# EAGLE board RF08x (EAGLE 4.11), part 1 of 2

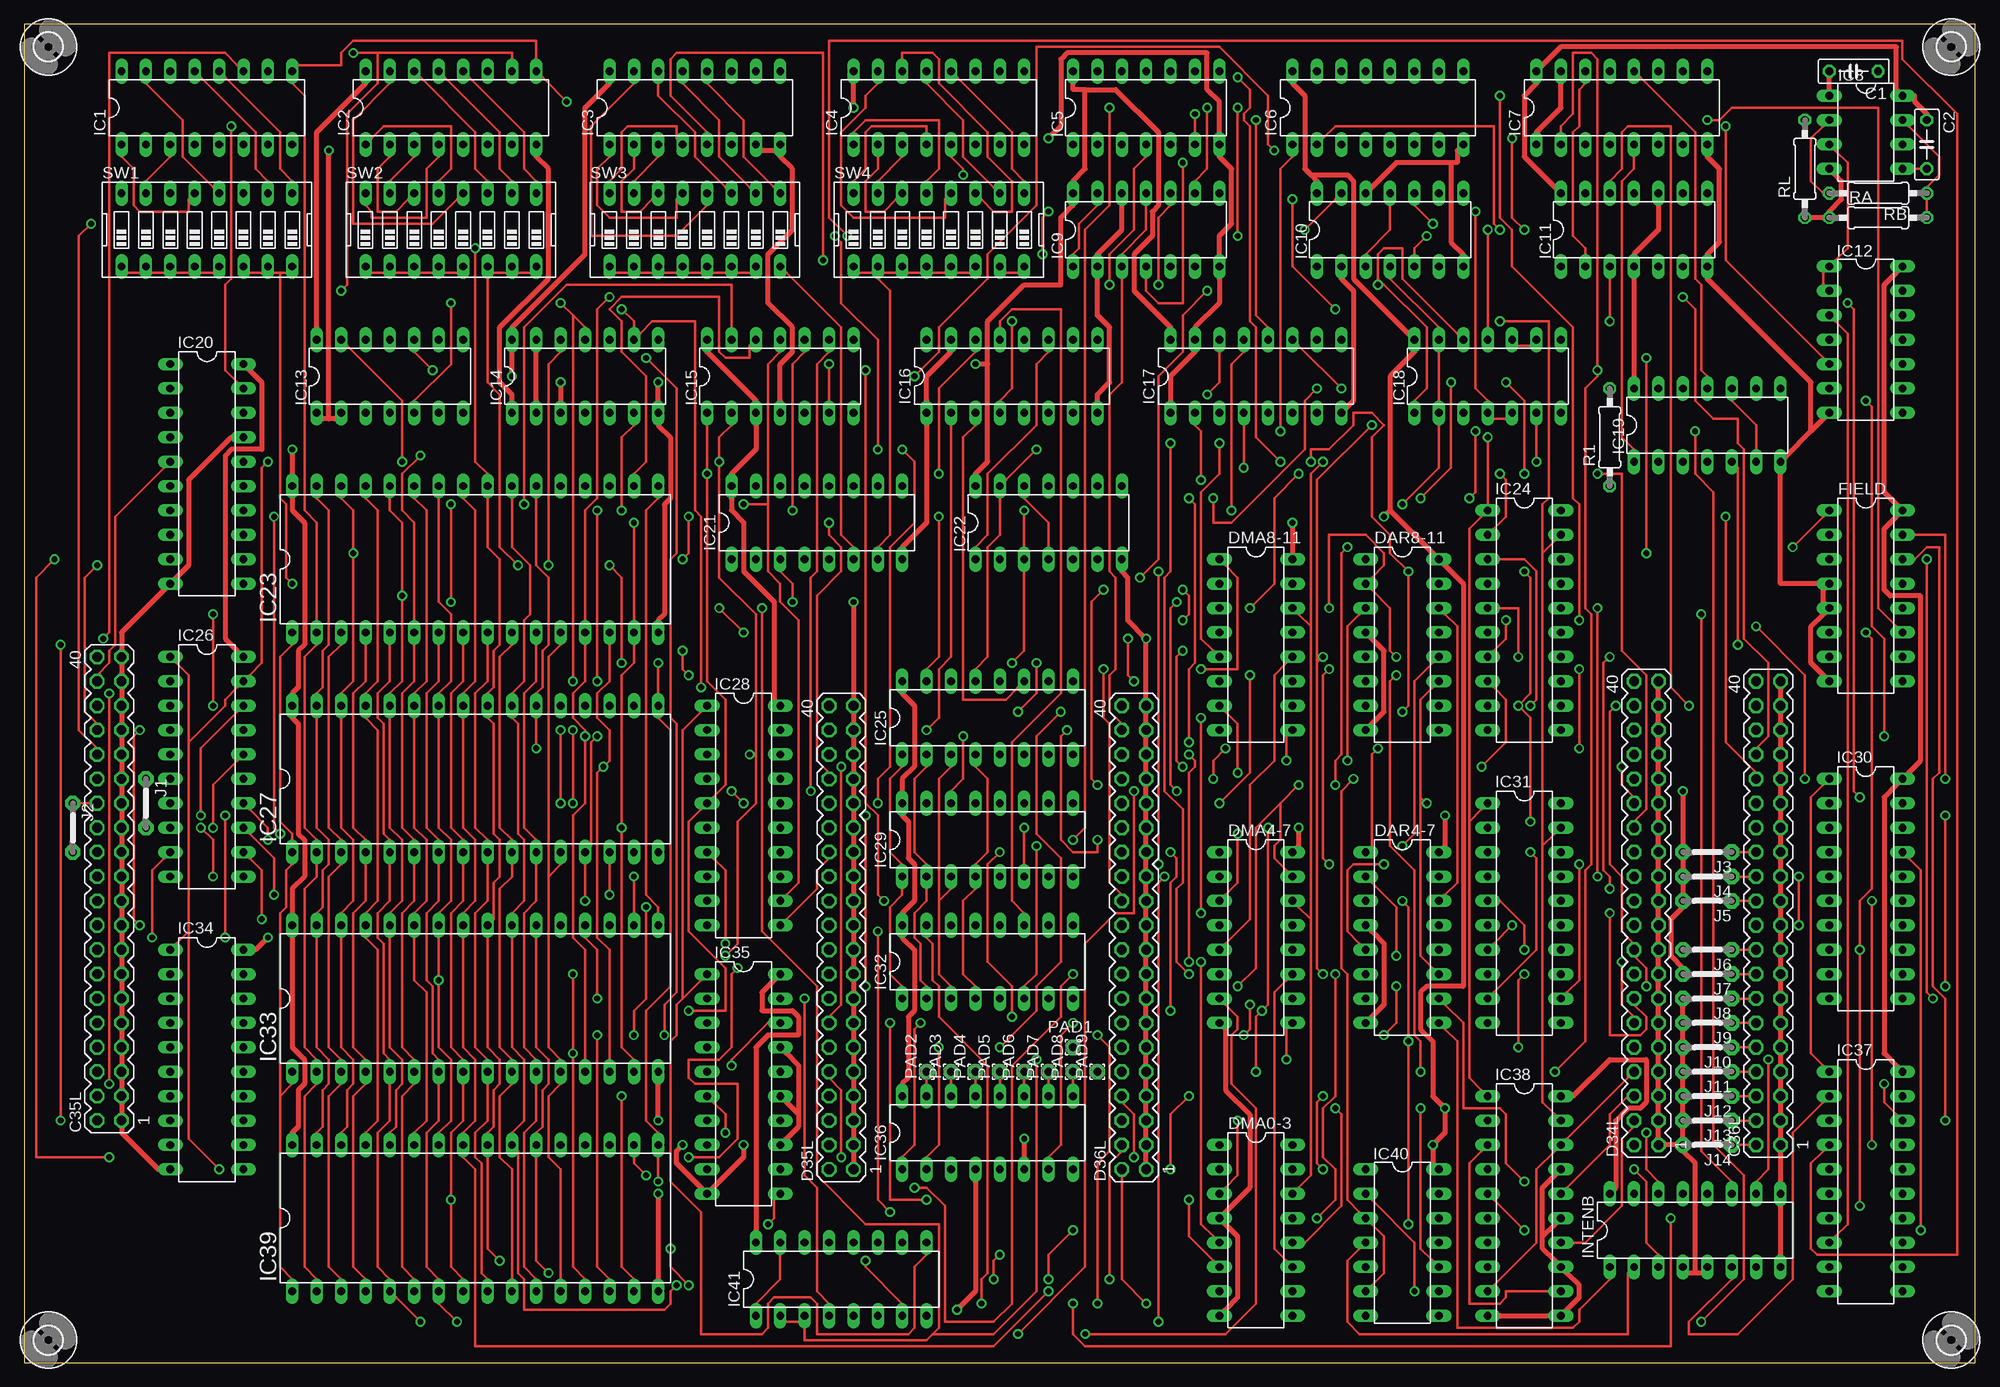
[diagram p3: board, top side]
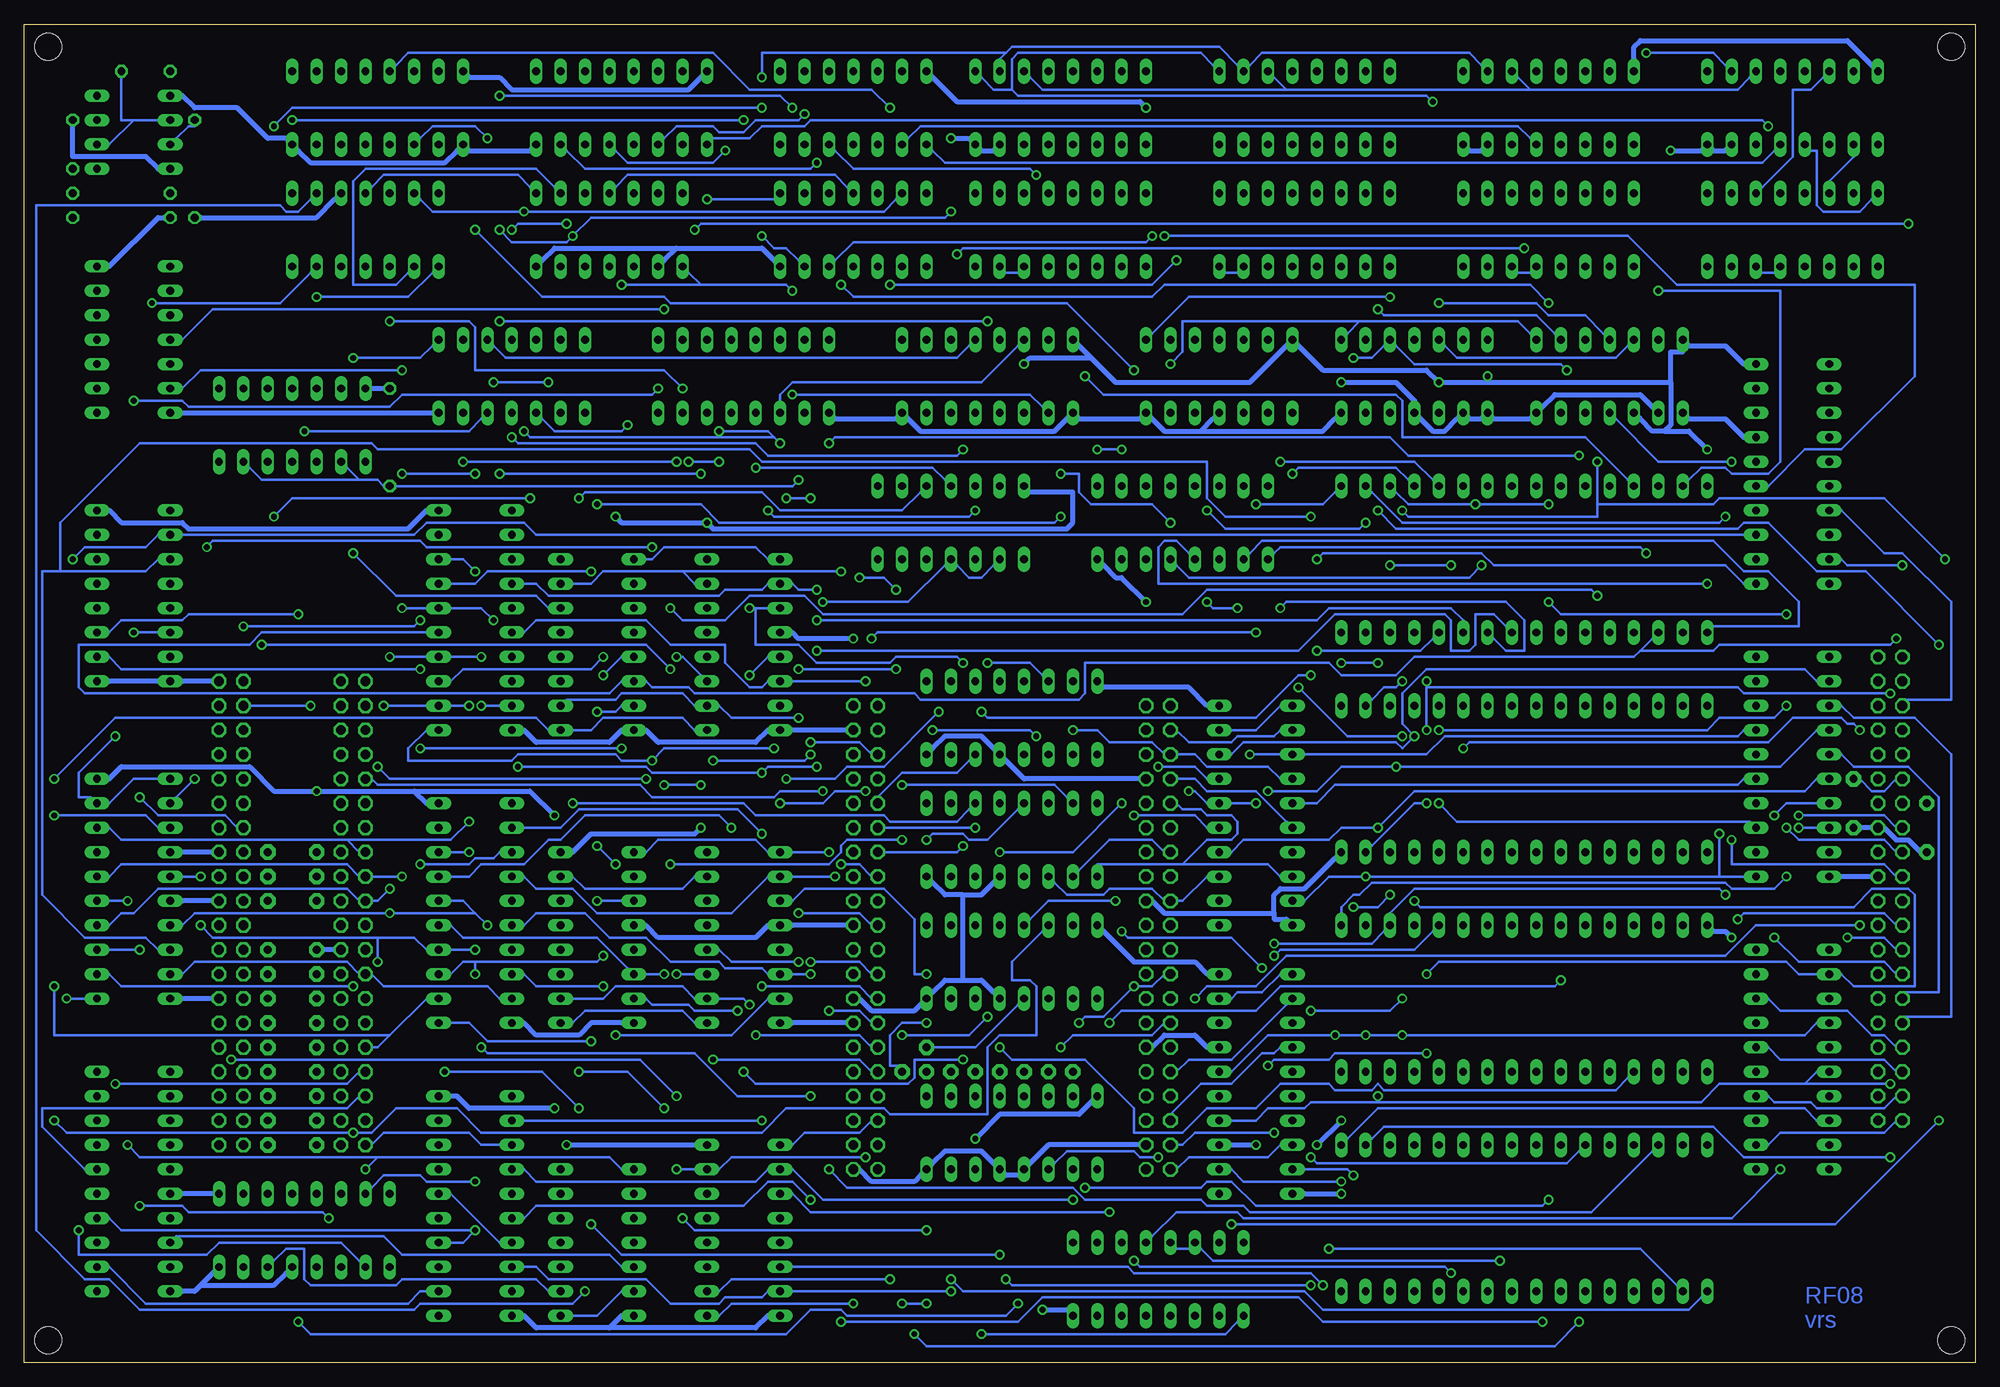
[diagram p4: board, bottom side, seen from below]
Size 203.18 x 139.37 mm. Coordinates in mm from the lower left corner, seen from the top.
Outline: 0,0 203.18,0 203.18,139.37 0,139.37 0,0
Copper layers (1*16): Top 0.035mm / dielectric 1.5mm / Bottom 0.035mm
Design rules "default": minimum track width 10mil, minimum drill 24mil, track to track 8mil, track to pad 8mil, pad to pad 8mil, via to via 8mil, smd to smd 8mil, copper to edge 40mil, drill to drill 8mil, minimum pad ring 10mil, minimum via ring 8mil, stop-mask expansion 4mil, vias tented up to drill 0mil, thermal gap 10mil
Net classes: 1 Power: width 0.508 mm

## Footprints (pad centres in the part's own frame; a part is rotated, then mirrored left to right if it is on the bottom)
C050-025X075 = drill 0.813 octagon: 1 -2.54,0; 2 2.54,0
MA20-2 = drill 1.016 octagon: 1 -24.13,-1.27; 2 -24.13,1.27; 3 -21.59,-1.27; 4 -21.59,1.27; 5 -19.05,-1.27; 6 -19.05,1.27; 7 -16.51,-1.27; 8 -16.51,1.27; 9 -13.97,-1.27; 10 -13.97,1.27; 11 -11.43,-1.27; 12 -11.43,1.27; 13 -8.89,-1.27; 14 -8.89,1.27; 15 -6.35,-1.27; 16 -6.35,1.27; 17 -3.81,-1.27; 18 -3.81,1.27; 19 -1.27,-1.27; 20 -1.27,1.27; 21 1.27,-1.27; 22 1.27,1.27; 23 3.81,-1.27; 24 3.81,1.27; 25 6.35,-1.27; 26 6.35,1.27; 27 8.89,-1.27; 28 8.89,1.27; 29 11.43,-1.27; 30 11.43,1.27; 31 13.97,-1.27; 32 13.97,1.27; 33 16.51,-1.27; 34 16.51,1.27; 35 19.05,-1.27; 36 19.05,1.27; 37 21.59,-1.27; 38 21.59,1.27; 39 24.13,-1.27; 40 24.13,1.27
DIL16 = drill 0.813 long: 1 -8.89,-3.81; 2 -6.35,-3.81; 3 -3.81,-3.81; 4 -1.27,-3.81; 5 1.27,-3.81; 6 3.81,-3.81; 7 6.35,-3.81; 8 8.89,-3.81; 9 8.89,3.81; 10 6.35,3.81; 11 3.81,3.81; 12 1.27,3.81; 13 -1.27,3.81; 14 -3.81,3.81; 15 -6.35,3.81; 16 -8.89,3.81
DIL14 = drill 0.813 long: 1 -7.62,-3.81; 2 -5.08,-3.81; 3 -2.54,-3.81; 4 0,-3.81; 5 2.54,-3.81; 6 5.08,-3.81; 7 7.62,-3.81; 8 7.62,3.81; 9 5.08,3.81; 10 2.54,3.81; 11 0,3.81; 12 -2.54,3.81; 13 -5.08,3.81; 14 -7.62,3.81
DIL08 = drill 0.813 long: 1 -3.81,-3.81; 2 -1.27,-3.81; 3 1.27,-3.81; 4 3.81,-3.81; 5 3.81,3.81; 6 1.27,3.81; 7 -1.27,3.81; 8 -3.81,3.81
DIL20 = drill 0.813 long: 1 -11.43,-3.81; 2 -8.89,-3.81; 3 -6.35,-3.81; 4 -3.81,-3.81; 5 -1.27,-3.81; 6 1.27,-3.81; 7 3.81,-3.81; 8 6.35,-3.81; 9 8.89,-3.81; 10 11.43,-3.81; 11 11.43,3.81; 12 8.89,3.81; 13 6.35,3.81; 14 3.81,3.81; 15 1.27,3.81; 16 -1.27,3.81; 17 -3.81,3.81; 18 -6.35,3.81; 19 -8.89,3.81; 20 -11.43,3.81
DIL32 = drill 0.813 long: 1 -19.05,-7.62; 2 -16.51,-7.62; 3 -13.97,-7.62; 4 -11.43,-7.62; 5 -8.89,-7.62; 6 -6.35,-7.62; 7 -3.81,-7.62; 8 -1.27,-7.62; 9 1.27,-7.62; 10 3.81,-7.62; 11 6.35,-7.62; 12 8.89,-7.62; 13 11.43,-7.62; 14 13.97,-7.62; 15 16.51,-7.62; 16 19.05,-7.62; 17 19.05,7.62; 18 16.51,7.62; 19 13.97,7.62; 20 11.43,7.62; 21 8.89,7.62; 22 6.35,7.62; 23 3.81,7.62; 24 1.27,7.62; 25 -1.27,7.62; 26 -3.81,7.62; 27 -6.35,7.62; 28 -8.89,7.62; 29 -11.43,7.62; 30 -13.97,7.62; 31 -16.51,7.62; 32 -19.05,7.62
05 = drill 0.813 pad 1.6 octagon: 1 -2.54,0; 2 2.54,0
1,6/0,8 = drill 0.813 pad 1.6 octagon: 1 0,0
0207/10 = drill 0.813 octagon: 1 -5.08,0; 2 5.08,0
EDG-08 = drill 0.813 long: 1 -8.89,-3.81; 2 -6.35,-3.81; 3 -3.81,-3.81; 4 -1.27,-3.81; 5 1.27,-3.81; 6 3.81,-3.81; 7 6.35,-3.81; 8 8.89,-3.81; 9 8.89,3.81; 10 6.35,3.81; 11 3.81,3.81; 12 1.27,3.81; 13 -1.27,3.81; 14 -3.81,3.81; 15 -6.35,3.81; 16 -8.89,3.81
2,8 = hole 2.8: 0,0

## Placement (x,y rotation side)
C1  .1uf  [C050-025X075]  190.5,134.46 180 top
C2  .1uf  [C050-025X075]  198.12,126.83 270 top
C35L  [MA20-2]  8.88,49.37 90 top
C36L  [MA20-2]  181.61,46.83 90 top
D34L  [MA20-2]  168.91,46.83 90 top
D35L  [MA20-2]  85.09,44.29 90 top
D36L  [MA20-2]  115.56,44.29 90 top
DAR4-7  74LS193N  [DIL16]  143.5,44.29 270 top
DAR8-11  74LS193N  [DIL16]  143.5,74.77 270 top
DMA0-3  74LS193N  [DIL16]  128.27,13.81 270 top
DMA4-7  74LS193N  [DIL16]  128.27,44.29 270 top
DMA8-11  74LS193N  [DIL16]  128.27,74.77 270 top
FIELD  74LS193N  [DIL16]  191.77,79.84 270 top
IC1  74LS151N  [DIL16]  19.05,130.65 0 top
IC2  74LS151N  [DIL16]  44.45,130.65 0 top
IC3  74LS151N  [DIL16]  69.84,130.65 0 top
IC4  74LS151N  [DIL16]  95.25,130.65 0 top
IC5  74LS20N  [DIL14]  116.84,130.65 0 top
IC6  74S139N  [DIL16]  140.97,130.65 0 top
IC7  74LS139N  [DIL16]  166.37,130.65 0 top
IC8  LM555N  [DIL08]  191.77,128.11 270 top
IC9  74S74N  [DIL14]  116.84,117.94 0 top
IC10  74S74N  [DIL14]  142.24,117.94 0 top
IC11  74S74N  [DIL14]  167.63,117.94 0 top
IC12  74LS00N  [DIL14]  191.77,106.52 270 top
IC13  74180N  [DIL14]  38.09,102.7 0 top
IC14  74180N  [DIL14]  58.41,102.7 0 top
IC15  74180N  [DIL14]  78.73,102.7 0 top
IC16  74S139N  [DIL16]  102.87,102.7 0 top
IC17  74S139N  [DIL16]  128.27,102.7 0 top
IC18  74LS00N  [DIL14]  152.4,102.7 0 top
IC19  7407N  [DIL14]  175.25,97.62 0 top
IC20  74S240N  [DIL20]  19.05,92.54 270 top
IC21  74LS139N  [DIL16]  82.55,87.46 0 top
IC22  7407N  [DIL14]  106.68,87.46 0 top
IC23  628512  [DIL32]  46.98,83.65 0 top
IC24  74S240N  [DIL20]  156.21,77.3 270 top
IC25  74S138N  [DIL16]  100.33,67.14 0 top
IC26  74S240N  [DIL20]  19.05,62.06 270 top
IC27  628512  [DIL32]  46.98,60.8 0 top
IC28  74LS244N  [DIL20]  74.93,56.98 270 top
IC29  74S138N  [DIL16]  100.33,54.45 0 top
IC30  74S240N  [DIL20]  191.77,49.37 270 top
IC31  74S240N  [DIL20]  156.21,46.83 270 top
IC32  74S138N  [DIL16]  100.33,41.74 0 top
IC33  628512  [DIL32]  46.98,37.94 0 top
IC34  74S240N  [DIL20]  19.05,31.59 270 top
IC35  74LS244N  [DIL20]  74.93,29.05 270 top
IC36  74S138N  [DIL16]  100.33,23.96 0 top
IC37  74S240N  [DIL20]  191.77,18.89 270 top
IC38  74S240N  [DIL20]  156.21,16.35 270 top
IC39  628512  [DIL32]  46.98,15.08 0 top
IC40  74S03N  [DIL14]  143.5,12.54 270 top
IC41  74LS139N  [DIL16]  85.09,8.73 0 top
INTENB  74LS193N  [DIL16]  173.99,13.81 0 top
J1  J5MM  [05]  12.69,58.26 270 top
J2  J5MM  [05]  5.08,55.72 270 top
J3  J5MM  [05]  175.25,53.18 180 top
J4  J5MM  [05]  175.25,50.63 180 top
J5  J5MM  [05]  175.25,48.09 180 top
J6  J5MM  [05]  175.25,43.02 180 top
J7  J5MM  [05]  175.25,40.48 180 top
J8  J5MM  [05]  175.25,37.94 180 top
J9  J5MM  [05]  175.25,35.4 180 top
J10  J5MM  [05]  175.25,32.86 180 top
J11  J5MM  [05]  175.25,30.32 180 top
J12  J5MM  [05]  175.25,27.78 180 top
J13  J5MM  [05]  175.25,25.23 180 top
J14  J5MM  [05]  175.25,22.7 180 top
PAD1  [1,6/0,8]  109.22,32.86 90 top
PAD2  [1,6/0,8]  93.98,30.32 90 top
PAD3  [1,6/0,8]  96.52,30.32 90 top
PAD4  [1,6/0,8]  99.06,30.32 90 top
PAD5  [1,6/0,8]  101.59,30.32 90 top
PAD6  [1,6/0,8]  104.14,30.32 90 top
PAD7  [1,6/0,8]  106.68,30.32 90 top
PAD8  [1,6/0,8]  109.22,30.32 90 top
PAD9  [1,6/0,8]  111.76,30.32 90 top
R1  5.1K  [0207/10]  165.09,96.35 90 top
RA  470K  [0207/10]  193.03,119.21 0 top
RB  1.5K  [0207/10]  193.03,121.75 180 top
RL  1K  [0207/10]  185.41,124.29 90 top
SW1  [EDG-08]  19.05,117.94 0 top
SW2  [EDG-08]  44.45,117.94 0 top
SW3  [EDG-08]  69.84,117.94 0 top
SW4  [EDG-08]  95.25,117.94 0 top
U$1  [2,8]  2.54,137 0 top
U$2  [2,8]  200.66,137 0 top
U$3  [2,8]  2.54,2.38 0 top
U$4  [2,8]  200.66,2.38 0 top

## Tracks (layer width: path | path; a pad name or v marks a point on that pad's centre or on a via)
3CYC\
  Top 0.254: C35L.28 6.98,58.26 5.71,58.26 J2.1
601\  (via drill 0.61)
  Top 0.254: IC9.1 109.22,115.4 109.85,116.04 109.85,118.58 111.76,120.48 IC9.13 | v99.69,6.18 99.69,8.73 100.33,9.36 100.33,30.95 95.25,36.03 95.25,39.2 94.61,39.84 94.61,43.65 93.98,44.29 IC32.15 | v174.62,4.28 179.06,8.73 179.06,19.52 175.89,22.7 175.89,90.64 173.99,92.54 v173.99,96.99 | IC18.5 154.3,98.26 153.03,98.26 IC18.4 152.4,100.16 151.12,101.43 v151.12,119.85
  Bottom 0.254: IC11.13 161.92,121.12 160.65,119.85 v151.12,119.85 113.66,119.85 112.39,121.12 IC9.13 | v99.69,6.18 100.96,4.92 117.47,4.92 118.11,5.55 121.28,5.55 123.82,3.01 173.35,3.01 v174.62,4.28 | v173.99,96.99 156.84,96.99 155.57,98.26 IC18.5
602\  (via drill 0.61)
  Top 0.254: 141.6,112.23 140.97,112.86 140.97,115.4 141.6,116.04 143.5,116.04 143.5,112.86 149.22,107.15 IC18.12 | 141.6,112.23 146.05,107.78 146.05,101.43 144.78,100.16 IC18.1 | v111.76,60.16 111.12,60.8 111.12,79.21 v112.39,80.48 | v116.2,81.75 118.11,83.65 118.11,102.7 120.65,105.24 120.65,109.05 v123.19,111.59 | 141.6,112.23 v140.97,112.23
  Bottom 0.254: v111.76,60.16 95.88,60.16 94.61,58.89 IC29.15 | v112.39,80.48 113.66,81.75 v116.2,81.75 | v123.19,111.59 123.82,112.23 132.71,112.23 | 132.71,112.23 133.98,113.5 IC10.1 | v140.97,112.23 132.71,112.23
604\  (via drill 0.61)
  Top 0.254: v95.25,88.1 95.25,73.49 93.98,72.22 IC25.15 | v143.5,89.37 147.31,93.18 147.31,97.62 IC18.2 147.31,100.16 147.31,105.24 IC18.13 147.31,107.78 142.24,112.86 IC10.4
  Bottom 0.254: v95.25,88.1 95.88,87.46 130.81,87.46 132.71,89.37 v143.5,89.37
611\  (via drill 0.61)
  Top 0.254: v168.91,23.96 168.91,20.16 170.18,18.89 INTENB.14 | v200.02,25.23 200.02,37.94 198.75,39.2 198.75,60.8 199.38,61.43 199.38,84.92 198.12,84.92 196.84,83.65 FIELD.14
  Bottom 0.254: IC32.14 97.15,44.92 100.33,41.74 100.33,39.84 98.42,39.84 97.79,39.2 97.79,34.12 101.59,34.12 102.87,32.86 102.87,25.87 113.03,25.87 113.66,26.51 123.82,26.51 126.36,23.96 155.57,23.96 158.11,26.51 164.46,26.51 167,23.96 v168.91,23.96 198.75,23.96 v200.02,25.23
612\  (via drill 0.61)
  Top 0.254: v97.79,65.24 97.79,60.8 96.52,59.52 IC29.14 | v108.58,65.88 107.95,65.24 107.95,54.45 109.22,53.18 111.76,53.18 v111.76,54.45 | v135.88,51.91 135.25,52.54 135.25,71.59 v135.88,72.22 | v178.43,74.77 178.43,93.18 IC19.5
  Bottom 0.254: v97.79,65.24 98.42,65.88 v108.58,65.88 | v111.76,54.45 117.47,54.45 118.11,53.81 118.11,53.18 119.38,51.91 v135.88,51.91 | v135.88,72.22 138.43,74.77 v178.43,74.77
614\  (via drill 0.61)
  Top 0.254: v102.87,72.86 104.14,74.13 104.14,82.38 IC22.3 104.14,84.92 v104.14,88.73 | v125.73,88.73 125.73,103.97 127,105.24 IC17.13
  Bottom 0.254: v102.87,72.86 98.42,72.86 97.15,71.59 IC25.14 | v125.73,88.73 125.09,88.1 104.77,88.1 v104.14,88.73
621\  (via drill 0.61)
  Top 0.254: v89.53,48.09 88.9,48.73 88.9,56.98 87.62,58.26 v87.62,103.34 | v156.21,117.94 154.94,119.21 v154.94,127.47
  Bottom 0.254: v89.53,48.09 96.52,48.09 98.42,46.19 IC32.13 | v87.62,103.34 94.61,110.32 135.88,110.32 136.52,110.96 149.22,110.96 v156.21,117.94 | v154.94,127.47 156.21,128.74 160.65,128.74 161.92,127.47 IC7.3
622\  (via drill 0.61)
  Top 0.254: v109.22,54.45 110.48,55.72 110.48,117.94 113.03,120.48 v113.03,130.65
  Bottom 0.254: v109.22,54.45 108.58,55.08 105.41,55.08 104.77,54.45 102.87,54.45 99.69,57.62 IC29.13 | v113.03,130.65 114.93,132.55 127.63,132.55 131.44,136.36 163.19,136.36 164.46,135.09 IC7.13
624\  (via drill 0.61)
  Top 0.254: IC25.13 99.06,72.22 100.33,73.49 100.33,84.92 101.59,86.19 101.59,90 IC22.13 102.23,91.91 v105.41,95.08 | 150.49,56.35 150.49,29.68 151.76,28.41 IC38.1 | 150.49,56.35 151.76,57.62 IC31.1 | 150.49,56.35 150.49,86.83 151.76,88.1 IC24.1 152.4,89.37 v152.4,96.35
  Bottom 0.254: v105.41,95.08 106.04,94.45 125.73,94.45 127,95.72 151.76,95.72 v152.4,96.35
641\
  Top 0.254: IC16.13 101.59,107.78 101.59,108.42 102.87,109.69 107.95,109.69 107.95,69.68 102.87,64.6 102.87,48.09 104.14,46.83 IC32.11
642\  (via drill 0.61)
  Top 0.254: v146.05,58.26 145.41,58.89 | 145.41,58.89 145.41,69.05 146.68,70.32 DAR8-11.11 | 145.41,58.89 145.41,42.38 146.68,41.11 DAR4-7.11
  Bottom 0.254: v146.05,58.26 128.27,58.26 127,56.98 113.66,56.98 113.03,56.35 106.04,56.35 104.77,57.62 IC29.11
644\
  Top 0.254: IC25.11 103.5,70.32 102.23,69.05 97.79,69.05 97.79,96.35 99.06,97.62 IC16.3
645\  (via drill 0.61)
  Top 0.254: 158.11,53.81 158.11,27.14 159.38,25.87 IC38.19 | 158.11,53.81 159.38,55.08 IC31.19 | 158.11,84.29 159.38,85.56 IC24.19 | 158.11,84.29 158.11,53.81 | v102.87,108.42 102.87,101.43 101.59,100.16 IC16.4 | v153.66,108.42 158.75,108.42 158.75,90 158.11,89.37 158.11,84.29
  Bottom 0.254: v153.66,108.42 v102.87,108.42
ACB00\
  Top 0.254: IC38.12 158.75,7.46 154.3,7.46 154.3,6.82 153.66,6.18 150.49,6.18 150.49,20.79 151.76,22.06 IC38.3
  Bottom 0.254: IC37.12 194.31,10 190.5,6.18 163.19,6.18 161.92,7.46 161.28,7.46 IC38.12 | D34L.2 167,22.7 165.73,23.96 156.84,23.96 155.57,22.7 153.66,22.7 IC38.3
ACB01\  (via drill 0.61)
  Top 0.254: v156.21,13.81 153.03,16.98 IC38.5 | D34L.4 167.63,24.6 166.37,23.33 166.37,16.35 162.56,12.54 161.28,12.54 IC38.14
  Bottom 0.254: IC38.14 158.75,12.54 157.47,12.54 v156.21,13.81 193.03,13.81 194.31,15.08 IC37.14
ACB02\
  Top 0.254: IC38.16 160.65,18.25 165.09,22.7 165.09,25.87 167,27.78 D34L.6
  Bottom 0.254: IC38.7 153.66,12.54 158.75,17.62 IC38.16 | IC37.16 196.84,20.16 201.29,24.6 201.29,26.51 169.54,26.51 168.27,27.78 D34L.6
ACB03\  (via drill 0.61)
  Top 0.254: IC38.9 153.03,8.09 157.47,12.54 157.47,20.16 159.38,22.06 IC38.18 160.65,23.33 167,29.68 167,30.32 D34L.8 | v193.67,29.05 193.67,27.14 194.94,25.87 IC37.18
  Bottom 0.254: v193.67,29.05 169.54,29.05 168.27,30.32 D34L.8
ACB04\  (via drill 0.61)
  Top 0.254: v161.92,51.91 161.92,39.84 160.65,38.57 IC31.12 | v200.02,56.98 v200.02,39.2
  Bottom 0.254: 165.09,34.12 166.37,32.86 167,32.86 D34L.10 | 165.09,34.12 161.28,37.94 IC31.12 | v161.92,51.91 156.84,51.91 156.21,52.54 154.3,52.54 153.66,53.18 IC31.3 | v200.02,56.98 190.5,56.98 189.22,55.72 IC30.3 | v200.02,39.2 200.02,34.12 165.09,34.12
ACB05\  (via drill 0.61)
  Top 0.254: v156.21,43.02 156.21,45.55 153.66,48.09 IC31.5 | v184.78,45.55 v184.78,50.63 | v166.37,41.74 166.37,37.3 167.63,36.03 D34L.12
  Bottom 0.254: v156.21,43.02 158.75,43.02 IC31.14 161.28,43.02 162.56,44.29 166.37,44.29 | v184.78,50.63 186.69,50.63 IC30.5 | v184.78,45.55 183.51,44.29 166.37,44.29 | 166.37,44.29 v166.37,41.74
ACB06\  (via drill 0.61)
  Top 0.254: v154.94,45.55 153.03,43.65 IC31.7 | v165.09,46.83 165.09,34.12 168.27,34.12 168.91,34.76 168.91,36.03 167.63,37.3 D34L.14
  Bottom 0.254: 156.21,46.83 157.47,48.09 158.75,48.09 IC31.16 | v154.94,45.55 156.21,46.83 | 156.21,46.83 v165.09,46.83 185.41,46.83 186.69,45.55 IC30.7
ACB07\  (via drill 0.61)
  Top 0.254: v156.84,53.18 157.47,52.54 157.47,43.02 153.03,38.57 IC31.9
  Bottom 0.254: IC31.9 153.66,37.94 154.94,39.2 165.73,39.2 167,40.48 D34L.16 168.27,40.48 169.54,41.74 185.41,41.74 186.69,40.48 IC30.9 | v156.84,53.18 158.75,53.18 IC31.18
ACB08\  (via drill 0.61)
  Top 0.254: v156.84,68.41 157.47,69.05 157.47,82.38 156.21,83.65 153.66,83.65 IC24.3 | v168.91,39.2 168.91,41.11 167.63,42.38 D34L.18 167.63,43.65 166.37,44.92 166.37,50.63 165.09,51.91 165.09,67.78 v165.73,68.41
  Bottom 0.254: v156.84,68.41 158.75,68.41 IC24.12 161.28,68.41 v165.73,68.41 | v168.91,39.2 193.03,39.2 194.31,40.48 IC30.12
ACB09\  (via drill 0.61)
  Top 0.254: v155.57,73.49 155.57,78.57 153.66,78.57 IC24.5 | v165.09,73.49 164.46,72.86 164.46,51.27 165.09,50.63 v165.09,49.37
  Bottom 0.254: v155.57,73.49 158.75,73.49 IC24.14 161.28,73.49 v165.09,73.49 | IC30.14 194.31,45.55 193.03,46.83 191.77,46.83 189.22,49.37 169.54,49.37 168.27,48.09 D34L.22 167,48.09 166.37,48.09 v165.09,49.37
ACB10\  (via drill 0.61)
  Top 0.254: v154.3,77.3 154.3,75.4 153.03,74.13 IC24.7 | v163.83,50.63 v163.83,78.57
  Bottom 0.254: v154.3,77.3 155.57,78.57 158.75,78.57 IC24.16 161.28,78.57 v163.83,78.57 | IC30.16 194.31,50.63 193.03,51.91 169.54,51.91 168.27,50.63 D34L.24 167,50.63 v163.83,50.63
ACB11\  (via drill 0.61)
  Top 0.254: v156.21,82.38 156.84,81.75 156.84,69.68 v155.57,68.41 156.84,67.14 v156.84,56.35
  Bottom 0.254: v155.57,68.41 153.66,68.41 IC24.9 | v156.21,82.38 157.47,83.65 158.75,83.65 IC24.18 | 169.54,54.45 193.03,54.45 194.31,55.72 IC30.18 | 169.54,54.45 168.27,53.18 D34L.26 | v156.84,56.35 158.75,54.45 169.54,54.45
ACCLEAR\  (via drill 0.61)
  Top 0.254: IC22.12 104.14,90 106.68,87.46 106.68,84.92 IC22.4 | v120.01,59.52 119.38,60.16 119.38,78.57 v120.01,79.21
  Bottom 0.254: IC22.2 102.23,83.02 103.5,81.75 104.77,81.75 106.04,83.02 IC22.4 107.31,83.02 111.12,79.21 v120.01,79.21 | v120.01,59.52 124.45,59.52 125.09,58.89 137.79,58.89 139.06,60.16 166.37,60.16 167,60.8 D34L.32
BAC00  (via drill 0.61)
  Top 0.254: v116.84,6.18 114.3,8.73 114.3,19.52 D36L.2
  Bottom 0.254: v116.84,6.18 129.53,6.18 130.81,4.92 DMA0-3.9
BAC01  (via drill 0.61)
  Top 0.254: v113.03,8.73 113.03,20.79 114.3,22.06 D36L.4
  Bottom 0.254: v113.03,8.73 129.53,8.73 130.81,7.46 DMA0-3.10
BAC02
  Bottom 0.254: DMA0-3.1 123.19,22.7 121.92,23.96 116.2,23.96 114.93,25.23 D36L.6
BAC03  (via drill 0.61)
  Top 0.254: v115.56,21.43 115.56,25.87 114.3,27.14 D36L.8 | v181.61,31.59 181.61,20.16 180.34,18.89 INTENB.10 | v135.25,27.78 134.62,27.14 134.62,20.79 v135.25,20.16
  Bottom 0.254: v115.56,21.43 129.53,21.43 130.81,20.16 DMA0-3.15 133.34,20.16 v135.25,20.16 | v181.61,31.59 139.06,31.59 v135.25,27.78
BAC04  (via drill 0.61)
  Top 0.254: INTENB.1 165.09,8.73 161.92,5.55 161.92,4.28 161.28,3.65 149.22,3.65 149.22,33.49 147.95,34.76 DAR4-7.9 | v131.44,31.59 131.44,34.76 DMA4-7.9
  Bottom 0.254: DMA4-7.9 133.34,35.4 134.62,36.66 144.78,36.66 146.05,35.4 DAR4-7.9 | v131.44,31.59 116.2,31.59 114.93,30.32 D36L.10
BAC05  (via drill 0.61)
  Top 0.254: v156.21,18.89 154.3,20.79 154.3,25.87 153.66,26.51 149.86,26.51 149.86,35.4 147.95,37.3 DAR4-7.10 | v127,34.12 127.63,34.76 v127.63,37.3
  Bottom 0.254: DAR4-7.10 146.05,37.94 142.87,37.94 141.6,39.2 134.62,39.2 133.34,37.94 DMA4-7.10 130.81,37.94 128.27,37.94 v127.63,37.3 | v156.21,18.89 161.28,18.89 161.92,19.52 165.73,19.52 167,18.25 INTENB.15 | v127,34.12 116.2,34.12 114.93,32.86 D36L.12
BAC06  (via drill 0.61)
  Top 0.254: v161.92,72.22 v161.92,63.97 | v140.97,63.97 140.33,63.34 140.33,53.81 DAR4-7.1 | v119.38,36.66 119.38,50 120.01,50.63 120.01,52.54 v119.38,53.18
  Bottom 0.254: DAR4-7.1 138.43,53.18 137.16,54.45 127,54.45 125.73,53.18 DMA4-7.1 123.19,53.18 v119.38,53.18 | v161.92,72.22 193.03,72.22 194.31,73.49 FIELD.10 | v161.92,63.97 v140.97,63.97 | v119.38,36.66 116.2,36.66 114.93,35.4 D36L.14
BAC07  (via drill 0.61)
  Top 0.254: v184.15,84.92 187.32,88.1 FIELD.1 | v137.79,84.92 137.16,84.29 137.16,63.34 136.52,62.7 v136.52,60.16 | v132.71,60.16 130.81,58.26 | 130.81,58.26 130.81,54.45 130.17,53.81 130.17,52.54 131.44,51.27 DMA4-7.15 | v126.36,39.2 128.27,41.11 128.27,55.72 130.81,58.26
  Bottom 0.254: DMA4-7.15 133.34,50.63 134.62,49.37 144.78,49.37 146.05,50.63 DAR4-7.15 | v184.15,84.92 183.51,85.56 161.92,85.56 161.28,84.92 v137.79,84.92 | v136.52,60.16 v132.71,60.16 | v126.36,39.2 116.2,39.2 114.93,37.94 D36L.16
BAC08  (via drill 0.61)
  Top 0.254: v200.02,60.8 200.02,86.19 196.84,86.19 FIELD.15 | v121.28,41.74 121.28,61.43 121.92,62.06 121.92,62.7 v121.28,63.34 | v131.44,62.7 131.44,65.24 DMA8-11.9
  Bottom 0.254: DMA8-11.9 133.34,65.88 134.62,67.14 142.87,67.14 144.14,65.88 146.05,65.88 DAR8-11.9 148.59,65.88 149.86,67.14 193.67,67.14 v200.02,60.8 | v121.28,41.74 116.2,41.74 114.93,40.48 D36L.18 | v121.28,63.34 121.92,62.7 v131.44,62.7
BAC09  (via drill 0.61)
  Top 0.254: v122.55,46.83 v122.55,67.14
  Bottom 0.254: DAR8-11.10 146.68,69.05 141.6,69.05 140.97,69.68 134.62,69.68 133.34,68.41 DMA8-11.10 130.81,68.41 129.53,67.14 v122.55,67.14 | v122.55,46.83 116.2,46.83 114.93,45.55 D36L.22
BAC10  (via drill 0.61)
  Top 0.254: v112.39,72.22 112.39,67.14 113.03,66.51 113.03,50 114.3,48.73 D36L.24 | v122.55,72.22 126.36,72.22 126.36,81.75 125.09,83.02 DMA8-11.1
  Bottom 0.254: DMA8-11.1 125.73,83.65 127,84.92 136.52,84.92 137.79,83.65 138.43,83.65 DAR8-11.1 | v112.39,72.22 v122.55,72.22
BAC11  (via drill 0.61)
  Top 0.254: v118.11,51.91 v118.11,82.38
  Bottom 0.254: 134.62,82.38 133.34,81.11 DMA8-11.15 | 134.62,82.38 142.87,82.38 144.14,81.11 146.05,81.11 DAR8-11.15 | v118.11,51.91 116.2,51.91 114.93,50.63 D36L.26 | v118.11,82.38 134.62,82.38
BADDAC\  (via drill 0.61)
  Top 0.254: v172.72,110.96 173.99,109.69 173.99,100.16 175.89,98.26 178.43,98.26 178.43,95.72 179.06,95.08 179.06,75.4 181.61,72.86 181.61,65.24 180.34,63.97 C36L.34
  Bottom 0.254: v172.72,110.96 163.19,110.96 160.65,113.5 IC11.1
BBREAK\  (via drill 0.61)
  Top 0.254: IC41.1 76.2,6.18 78.73,8.73 78.73,11.27 IC41.15 | v21.59,128.74 21.59,112.86 20.95,112.23 20.95,103.34 22.22,102.07 IC20.19 | v124.45,95.72 124.45,92.54 122.55,90.64 122.55,75.4 123.82,74.13 DMA8-11.5 | v130.81,96.99 130.81,124.29 132.08,125.56 IC6.1 | v177.16,88.1 177.16,64.6 180.34,61.43 C36L.32 | v150.49,90 151.12,90.64 v151.12,96.99 | v103.5,3.01 110.48,10 110.48,43.65 113.66,46.83 115.56,46.83 v115.56,59.52 | v124.45,58.26 127.63,61.43 v127.63,71.59
  Bottom 0.254: v21.59,128.74 22.22,129.38 121.28,129.38 121.92,128.74 126.36,128.74 127.63,127.47 131.44,127.47 IC6.1 | 125.09,96.35 125.73,96.99 v130.81,96.99 | 125.09,96.35 v124.45,95.72 | v177.16,88.1 175.25,90 v150.49,90 | v151.12,96.99 150.49,96.35 125.09,96.35 | v103.5,3.01 78.1,3.01 76.83,4.28 IC41.1 | v115.56,59.52 118.74,59.52 120.01,58.26 v124.45,58.26 | v127.63,71.59 125.73,73.49 DMA8-11.5
BINIT
  Top 0.254: IC10.3 139.69,115.4 142.24,117.94 142.24,120.48 IC10.11 | IC9.11 116.84,120.48 116.84,117.94 114.3,115.4 IC9.3 114.3,112.86 114.3,102.07 113.03,100.8 113.03,82.38 113.66,81.75 113.66,72.22 113.03,71.59 113.03,67.78 114.3,66.51 D36L.38
  Bottom 0.254: IC10.11 141.6,122.39 140.33,123.66 118.74,123.66 117.47,122.39 IC9.11
BINIT\  (via drill 0.61)
  Top 0.254: v173.35,68.41 171.44,70.32 171.44,128.74 167,128.74 166.37,128.11 166.37,124.29 165.09,123.02 IC11.12
  Bottom 0.254: v173.35,68.41 179.7,68.41 C36L.38
BIOP1  (via drill 0.61)
  Top 0.254: v105.41,53.81 105.41,40.48 104.14,39.2 IC32.6
  Bottom 0.254: v105.41,53.81 106.04,53.18 113.66,53.18 D36L.28
BIOP2  (via drill 0.61)
  Top 0.254: v104.14,55.72 104.14,51.91 IC29.6
  Bottom 0.254: v104.14,55.72 113.66,55.72 D36L.30
BIOP4
  Bottom 0.254: IC25.6 104.77,62.7 106.04,61.43 111.76,61.43 114.3,58.89 D36L.32
BMB00
  Bottom 0.254: IC35.8 72.39,22.7 73.66,21.43 81.91,21.43 83.18,20.16 D35L.2
BMB01  (via drill 0.61)
  Top 0.254: v73.02,23.96 73.02,25.87 71.75,27.14 IC35.6
  Bottom 0.254: v73.02,23.96 81.28,23.96 82.55,22.7 83.18,22.7 D35L.4
BMB02
  Bottom 0.254: IC35.4 72.39,32.86 73.02,32.22 74.29,32.22 77.47,29.05 80.64,29.05 83.81,25.87 D35L.6
BMB03  (via drill 0.61)
  Top 0.254: v85.09,21.43 85.09,28.41 83.81,29.68 D35L.10
  Bottom 0.254: IC35.2 71.75,37.3 77.47,31.59 81.91,31.59 83.18,30.32 D35L.10 | v85.09,21.43 86.99,21.43 87.62,22.06 94.61,22.06 95.88,20.79 IC36.3
BMB04  (via drill 0.61)
  Top 0.254: v95.25,32.86 95.25,22.7 93.98,21.43 IC36.2 | v85.09,62.06 85.09,37.3 83.81,36.03 D35L.14
  Bottom 0.254: v95.25,32.86 93.98,34.12 85.72,34.12 84.45,35.4 D35L.14 | v85.09,62.06 81.28,62.06 80.01,60.8 IC28.17
BMB05  (via drill 0.61)
  Top 0.254: v93.34,35.4 92.7,34.76 92.7,22.7 91.44,21.43 IC36.1 | v87.62,39.2 v87.62,56.98
  Bottom 0.254: v93.34,35.4 92.7,36.03 90.8,36.03 v87.62,39.2 85.72,39.2 84.45,40.48 D35L.18 | v87.62,56.98 81.28,56.98 80.01,55.72 IC28.15
BMB06
  Top 0.254: 95.25,48.09 95.25,40.48 96.52,39.2 IC32.3 | 95.25,48.09 96.52,49.37 IC29.3 | 95.25,48.09 95.25,60.8 96.52,62.06 IC25.3
  Bottom 0.254: IC28.13 80.01,50.63 82.55,48.09 83.18,48.09 D35L.24 84.45,48.09 85.72,49.37 90.17,49.37 90.8,48.73 94.61,48.73 95.88,50 IC29.3
BMB07
  Top 0.254: IC28.11 79.37,46.19 82.55,49.37 82.55,51.27 83.81,52.54 D35L.28 | IC32.2 93.98,39.2 93.34,39.84 93.34,43.65 92.7,44.29 92.7,46.83 93.98,48.09 93.98,49.37 IC29.2 93.98,51.91 92.7,53.18 92.7,60.8 93.98,62.06 IC25.2
  Bottom 0.254: D35L.28 84.45,53.18 85.72,54.45 90.17,54.45 93.34,51.27 IC29.2
BMB08
  Top 0.254: IC32.1 91.44,39.2 90.17,40.48 90.17,47.46 91.44,48.73 91.44,49.37 IC29.1 91.44,51.91 90.17,53.18 90.17,60.8 91.44,62.06 IC25.1
  Bottom 0.254: 82.55,51.91 91.44,51.91 IC29.1 | 82.55,51.91 73.66,51.91 72.39,50.63 IC28.8 | 82.55,51.91 80.01,54.45 77.47,54.45 76.83,55.08 76.83,56.35 77.47,56.98 80.01,56.98 80.64,57.62 82.55,57.62 83.18,58.26 D35L.32
BMB09  (via drill 0.61)
  Top 0.254: v83.81,87.46 83.81,86.19 85.09,84.92 85.09,82.38 82.55,79.84 82.55,62.7 83.81,61.43 D35L.34 | v95.25,92.54 95.25,101.43 99.06,105.24 IC16.14
  Bottom 0.254: IC28.6 71.75,56.35 74.93,59.52 80.01,59.52 81.28,60.8 83.18,60.8 D35L.34 | IC16.14 99.69,105.88 103.5,102.07 123.19,102.07 124.45,100.8 124.45,100.16 IC17.3 | v83.81,87.46 85.72,89.37 92.07,89.37 93.34,90.64 93.34,92.54 v95.25,92.54
BMB10  (via drill 0.61)
  Top 0.254: v123.19,100.8 124.45,102.07 124.45,105.24 IC17.14 | v93.98,65.88 95.25,67.14 95.25,72.22 96.52,73.49 96.52,97.62 IC16.2
  Bottom 0.254: IC28.4 72.39,60.8 73.66,62.06 80.01,62.06 81.28,63.34 83.18,63.34 D35L.36 84.45,63.34 85.72,64.6 90.17,64.6 91.44,65.88 v93.98,65.88 | v123.19,100.8 98.42,100.8 97.15,99.53 IC16.2
BMB11
  Bottom 0.254: IC28.2 72.39,65.88 73.02,65.24 76.83,65.24 77.47,64.6 81.91,64.6 83.18,65.88 D35L.38
BRK_RQ\  (via drill 0.61)
  Top 0.254: v189.86,110.32 190.5,109.69 190.5,59.52 v191.13,58.89
  Bottom 0.254: v189.86,110.32 176.53,110.32 173.35,113.5 IC11.6 | v191.13,58.89 189.22,56.98 182.24,56.98 180.97,55.72 C36L.28
BTS1  (via drill 0.61)
  Top 0.254: v165.09,108.42 165.09,112.86 IC11.3 | v134.62,101.43 133.34,100.16 133.34,95.08 125.73,87.46 123.82,87.46 v123.82,90 | v121.28,90 121.92,89.37 121.92,72.86 121.28,72.22 v121.28,64.6
  Bottom 0.254: v165.09,108.42 156.84,108.42 156.21,107.78 156.21,103.34 136.52,103.34 v134.62,101.43 | v123.82,90 v121.28,90 | v121.28,64.6 116.2,64.6 114.93,63.34 D36L.36
BUSY
  Top 0.254: IC7.14 162.56,133.19 161.92,132.55 161.92,128.74 161.28,128.11 161.28,117.31 162.56,116.04 162.56,115.4 IC11.2
  Bottom 0.254: IC10.9 147.95,122.39 149.86,124.29 167.63,124.29 168.91,123.02 168.91,112.23 164.46,112.23 163.19,113.5 IC11.2
BWCO\  (via drill 0.61)
  Top 0.254: v133.34,117.94 136.52,121.12 IC10.13 | v6.98,118.58 5.71,117.31 5.71,65.88 7.62,63.97 C35L.32
  Bottom 0.254: v133.34,117.94 132.71,118.58 v6.98,118.58
CA_INCR\
  Bottom 0.254: C35L.30 8.25,60.8 9.52,59.52 10.79,59.52 12.06,60.8 J1.1
CIE  (via drill 0.61)
  Top 0.254: v167.63,20.16 168.91,18.89 168.91,12.54 170.18,11.27 INTENB.3 | v192.4,22.7 v192.4,48.09
  Bottom 0.254: 166.37,21.43 142.24,21.43 140.97,20.16 IC40.1 | 166.37,21.43 v167.63,20.16 | v192.4,48.09 194.31,48.09 IC30.15 | v192.4,22.7 191.13,21.43 166.37,21.43
DA00\
  Top 0.254: C36L.2 179.7,22.7 178.43,22.7 J14.1
DA01\
  Top 0.254: C36L.4 179.7,25.23 178.43,25.23 J13.1
DA02\
  Top 0.254: C36L.6 179.7,27.78 178.43,27.78 J12.1
DA03\
  Top 0.254: C36L.8 179.7,30.32 178.43,30.32 J11.1
DA04\
  Top 0.254: C36L.10 179.7,32.86 178.43,32.86 J10.1
DA05\
  Top 0.254: C36L.12 179.7,35.4 178.43,35.4 J9.1
DA06\
  Top 0.254: C36L.14 179.7,37.94 178.43,37.94 J8.1
DA07\
  Top 0.254: C36L.16 179.7,40.48 178.43,40.48 J7.1
DA08\
  Top 0.254: C36L.18 179.7,43.02 178.43,43.02 J6.1
DA09\
  Top 0.254: C36L.22 179.7,48.09 178.43,48.09 J5.1
DA10\
  Top 0.254: C36L.24 179.7,50.63 178.43,50.63 J4.1
DA11\
  Top 0.254: C36L.26 179.7,53.18 178.43,53.18 J3.1
DAR04  (via drill 0.61)
  Top 0.254: v129.53,55.72 129.53,37.3 v128.9,36.66 128.27,36.03 v128.27,30.32 | IC41.2 79.37,4.28 80.64,4.28 IC41.3 81.28,3.65 81.28,2.38 93.98,2.38 94.61,3.01 | v80.01,79.21 80.01,81.11 78.73,82.38 IC21.3 | v76.83,78.57 76.83,44.92 82.55,39.2 82.55,19.52 87.62,14.44 95.25,14.44 95.25,3.65 94.61,3.01 | v105.41,31.59 105.41,7.46 100.96,3.01 94.61,3.01
  Bottom 0.254: v128.9,36.66 133.34,36.66 133.98,37.3 137.79,37.3 138.43,37.94 DAR4-7.7 | v129.53,55.72 130.81,56.98 144.78,56.98 147.31,54.45 148.59,54.45 151.12,51.91 155.57,51.91 156.84,50.63 158.75,50.63 IC31.17 | v80.01,79.21 79.37,78.57 v76.83,78.57 | v128.27,30.32 127,29.05 111.12,29.05 110.48,29.68 110.48,31.59 v105.41,31.59
DAR05  (via drill 0.61)
  Top 0.254: 26.67,27.78 26.67,10 27.94,8.73 IC39.1 | 26.67,27.78 27.94,29.05 IC33.1 | 26.67,27.78 26.67,46.83 27.3,47.46 27.3,51.27 27.94,51.91 IC27.1 27.94,54.45 27.94,55.08 26.67,56.35 26.67,73.49 27.94,74.77 IC23.1 | v136.52,40.48 136.52,27.78 135.25,26.51 135.25,21.43 136.52,20.16 136.52,16.98 v134.62,15.08 | v109.22,13.81 106.68,11.27 v106.68,8.73
  Bottom 0.254: IC31.15 158.75,45.55 157.47,44.29 143.5,44.29 140.33,41.11 DAR4-7.6 138.43,40.48 v136.52,40.48 | IC21.2 75.56,84.29 74.29,85.56 27.3,85.56 24.12,82.38 21.59,82.38 18.41,79.21 18.41,76.67 27.3,76.67 IC23.1 | v134.62,15.08 133.34,13.81 v109.22,13.81 | v106.68,8.73 105.41,7.46 69.84,7.46 67.94,5.55 29.84,5.55 28.57,6.82 IC39.1
DAR06  (via drill 0.61)
  Top 0.254: v142.87,42.38 142.87,47.46 140.33,50 DAR4-7.2 | IC39.30 33.02,23.96 33.65,24.6 33.65,28.41 34.28,29.05 34.28,31.59 33.02,32.86 33.02,44.29 IC33.30 33.02,46.83 34.28,48.09 34.28,54.45 33.02,55.72 33.02,67.14 IC27.30 33.02,69.68 34.28,70.95 v34.28,84.29 34.28,88.73 33.02,90 IC23.30 | v156.21,40.48 155.57,39.84 v155.57,32.86 | v121.28,27.78 119.38,25.87 v119.38,20.16
  Bottom 0.254: v142.87,42.38 143.5,41.74 156.21,41.74 | 156.21,41.74 157.47,41.74 158.75,40.48 IC31.13 | v34.28,84.29 34.92,84.92 72.39,84.92 73.02,84.29 IC21.1 | v156.21,40.48 156.21,41.74 | v155.57,32.86 154.94,32.22 133.34,32.22 128.9,27.78 v121.28,27.78 | v119.38,20.16 117.47,18.25 93.98,18.25 92.7,16.98 80.64,16.98 80.01,16.35 76.2,16.35 75.56,15.71 40,15.71 33.65,22.06 IC39.30
DAR07  (via drill 0.61)
  Top 0.254: v56.51,131.28 53.97,133.82 IC2.9 53.34,135.72 53.34,137.63 34.28,137.63 33.02,136.36 33.02,135.09 28.57,135.09 IC1.9 27.94,133.19 29.21,131.92 29.21,88.73 30.48,87.46 30.48,77.3 IC23.2 30.48,74.77 29.21,73.49 29.21,55.72 30.48,54.45 IC27.2 30.48,51.91 30.48,50.63 29.21,49.37 29.21,32.86 30.48,31.59 IC33.2 30.48,29.05 29.21,27.78 29.21,10 30.48,8.73 IC39.2 | v143.5,48.09 144.14,47.46 v144.14,33.49 v144.14,14.44 | v101.59,11.27 100.96,10.63 v100.96,8.73 | v69.21,8.09 67.31,10 v67.31,11.9
  Bottom 0.254: 100.33,132.55 100.33,135.72 99.69,136.36 80.64,136.36 79.37,135.09 IC3.9 | 100.33,132.55 102.23,132.55 103.5,133.82 IC4.9 | 100.33,132.55 99.69,131.92 57.14,131.92 v56.51,131.28 | v143.5,48.09 140.97,48.09 DAR4-7.3 | v144.14,33.49 154.94,33.49 156.84,35.4 158.75,35.4 IC31.11 | v144.14,14.44 140.97,11.27 v101.59,11.27 | v100.96,8.73 100.33,8.09 v69.21,8.09 | v67.31,11.9 34.92,11.9 31.11,8.09 IC39.2
DAR08  (via drill 0.61)
  Top 0.254: IC39.31 30.48,23.96 31.11,24.6 31.11,28.41 31.75,29.05 31.75,31.59 30.48,32.86 30.48,44.29 IC33.31 30.48,46.83 31.11,47.46 31.11,51.27 31.75,51.91 31.75,54.45 30.48,55.72 30.48,67.14 IC27.31 30.48,69.68 31.11,70.32 31.11,74.13 31.75,74.77 31.75,88.73 30.48,90 IC23.31 | v143.5,67.78 144.14,68.41 v144.14,82.38 142.24,84.29 142.24,86.19 140.33,88.1 140.33,96.35 141.6,97.62 140.33,98.89 138.43,98.89 138.43,97.62 135.88,95.08 133.98,95.08 v133.98,93.81 | 36.82,136.36 50.79,136.36 50.79,135.72 IC2.10 | 36.82,136.36 v34.28,136.36 | v130.81,93.81 128.27,96.35 128.27,107.78 127.63,108.42 127.63,128.74 127,129.38 127,130.01 127.63,130.65 127.63,132.55 v126.36,133.82 | v33.02,111.59 33.65,112.23 33.65,130.01 36.82,133.19 36.82,136.36
  Bottom 0.254: v143.5,67.78 141.6,67.78 140.97,68.41 DAR8-11.7 | v144.14,82.38 154.94,82.38 156.21,81.11 158.75,81.11 IC24.17 | v34.28,136.36 27.3,136.36 26.03,135.09 IC1.10 | IC2.10 51.43,135.09 52.7,136.36 74.29,136.36 75.56,135.09 IC3.10 76.83,135.09 78.73,137 100.33,137 100.96,136.36 | 100.96,136.36 101.59,135.72 IC4.10 | v130.81,93.81 v133.98,93.81 | v126.36,133.82 126.36,136.36 100.96,136.36 | v33.02,111.59 20.32,111.59 20.32,93.81 21.59,92.54 25.39,92.54 26.03,93.18 28.57,93.18 29.84,91.91 IC23.31
DAR09  (via drill 0.61)
  Top 0.254: IC39.3 33.02,8.73 31.75,10 31.75,27.78 33.02,29.05 IC33.3 33.02,31.59 31.75,32.86 31.75,50.63 33.02,51.91 IC27.3 33.02,54.45 31.75,55.72 31.75,73.49 33.02,74.77 IC23.3 | v8.25,75.4 8.88,76.03 8.88,136.36 20.95,136.36 22.22,135.09 IC1.11
  Bottom 0.254: 46.35,132.55 24.76,132.55 23.49,133.82 IC1.11 | 46.35,132.55 47.62,133.82 IC2.11 | 71.75,132.55 73.02,133.82 IC3.11 | 46.35,132.55 71.75,132.55 | 71.75,132.55 97.15,132.55 98.42,133.82 IC4.11 | IC24.15 161.28,76.03 178.43,76.03 179.7,74.77 197.48,74.77 197.48,70.32 196.84,69.68 142.24,69.68 140.97,70.95 DAR8-11.6 138.43,70.95 137.79,70.32 133.98,70.32 133.34,69.68 110.48,69.68 109.85,69.05 93.34,69.05 92.7,69.68 92.7,72.86 67.31,72.86 66.04,71.59 60.32,71.59 58.41,73.49 35.55,73.49 34.92,74.13 | 34.92,74.13 33.65,75.4 IC23.3 | v8.25,75.4 8.88,74.77 26.67,74.77 27.3,74.13 34.92,74.13
DAR10  (via drill 0.61)
  Top 0.254: v142.87,73.49 142.24,74.13 142.24,78.57 140.33,80.48 DAR8-11.2 140.33,81.75 141.6,83.02 141.6,84.29 139.69,86.19 135.88,86.19 v135.88,78.57 | IC39.28 38.09,23.96 38.73,24.6 38.73,28.41 39.36,29.05 39.36,31.59 38.09,32.86 38.09,44.29 IC33.28 38.09,46.83 39.36,48.09 39.36,54.45 38.09,55.72 38.09,67.14 IC27.28 38.09,69.68 39.36,70.95 v39.36,79.84 39.36,87.46 38.09,88.73 38.09,90 IC23.28
  Bottom 0.254: v142.87,73.49 144.14,72.22 157.47,72.22 158.75,70.95 IC24.13 | v135.88,78.57 134.62,77.3 130.17,77.3 127.63,79.84 121.92,79.84 120.01,77.94 82.55,77.94 80.01,80.48 40,80.48 v39.36,79.84
DAR11  (via drill 0.61)
  Top 0.254: v137.79,62.7 137.79,76.67 139.06,77.94 DAR8-11.3 | IC39.4 35.55,8.73 34.28,10 34.28,27.78 35.55,29.05 IC33.4 35.55,31.59 34.28,32.86 34.28,46.83 35.55,48.09 35.55,51.91 IC27.4 35.55,54.45 34.28,55.72 34.28,69.68 35.55,70.95 35.55,74.77 IC23.4 | v125.09,63.97 123.82,62.7 v123.82,60.8 | v107.95,67.78 105.41,65.24 105.41,55.08 107.95,52.54 107.95,41.74 105.41,39.2 105.41,36.66 v101.59,32.86
  Bottom 0.254: IC24.11 161.28,65.88 163.19,63.97 163.19,62.7 152.4,62.7 151.76,63.34 141.6,63.34 140.97,62.7 v137.79,62.7 136.52,63.97 v125.09,63.97 | v123.82,60.8 118.74,60.8 117.47,62.06 113.66,62.06 v107.95,67.78 | v101.59,32.86 100.33,31.59 92.7,31.59 87.62,26.51 87.62,23.96 82.55,23.96 80.01,26.51 74.93,26.51 72.39,29.05 67.31,29.05 66.67,28.41 62.86,28.41 62.22,29.05 61.59,28.41 37.46,28.41 36.19,29.68 IC33.4
DATA00\
  Bottom 0.254: IC34.12 21.59,22.7 20.32,23.96 9.52,23.96 8.25,25.23 C35L.2
DATA01\
  Bottom 0.254: IC34.14 21.59,27.78 20.95,27.14 17.14,27.14 16.51,26.51 9.52,26.51 8.25,27.78 C35L.4
DATA02\
  Bottom 0.254: IC34.16 21.59,32.86 20.32,31.59 9.52,31.59 8.25,30.32 C35L.6
DATA03\
  Bottom 0.254: IC34.18 21.59,37.94 20.32,36.66 13.33,36.66 10.79,34.12 9.52,34.12 8.25,32.86 C35L.8
DATA04\
  Bottom 0.254: IC26.3 13.96,68.41 12.69,67.14 6.34,67.14 2.54,63.34 2.54,36.03 7.62,36.03 C35L.10
DATA05\
  Bottom 0.254: IC26.5 13.96,63.34 12.69,62.06 6.98,62.06 3.81,58.89 3.81,38.57 7.62,38.57 C35L.12
DATA06\  (via drill 0.61)
  Top 0.254: v20.95,44.29 v20.95,56.98
  Bottom 0.254: v20.95,56.98 19.68,58.26 16.51,58.26 IC26.7 | v20.95,44.29 18.41,41.74 9.52,41.74 8.25,40.48 C35L.14
DATA07\  (via drill 0.61)
  Top 0.254: v13.33,44.29 13.33,51.27 14.6,52.54 IC26.9
  Bottom 0.254: v13.33,44.29 9.52,44.29 8.25,43.02 C35L.16
DATA08\  (via drill 0.61)
  Top 0.254: v24.76,46.19 24.76,51.27 23.49,52.54 IC26.12
  Bottom 0.254: v24.76,46.19 24.12,46.83 9.52,46.83 8.25,45.55 C35L.18
DATA09\  (via drill 0.61)
  Top 0.254: v25.39,54.45 25.39,55.72 23.49,57.62 IC26.14
  Bottom 0.254: v25.39,54.45 25.39,51.91 9.52,51.91 8.25,50.63 C35L.22
DATA10\  (via drill 0.61)
  Top 0.254: v19.68,55.72 19.68,60.16 22.22,62.7 IC26.16
  Bottom 0.254: v19.68,55.72 18.41,54.45 9.52,54.45 8.25,53.18 C35L.24
DATA11\  (via drill 0.61)
  Top 0.254: v18.41,56.98 18.41,63.97 22.22,67.78 IC26.18
  Bottom 0.254: v18.41,56.98 9.52,56.98 8.25,55.72 C35L.26
DCXA\
  Top 0.254: IC18.9 156.84,105.88 155.57,105.88 IC18.10
  Bottom 0.254: IC16.12 104.77,105.88 106.04,104.61 153.03,104.61 154.3,105.88 IC18.10
DIMA\  (via drill 0.61)
  Top 0.254: IC37.1 187.32,30.95 186.05,32.22 186.05,58.89 187.32,60.16 IC30.1 | v137.16,101.43 132.71,105.88 IC17.11 | v191.77,100.16 192.4,99.53 192.4,76.67 193.67,75.4 v193.67,65.24
  Bottom 0.254: IC30.1 189.22,60.8 191.77,60.8 194.31,58.26 IC30.19 196.21,58.89 197.48,58.89 197.48,61.43 v193.67,65.24 | v137.16,101.43 137.79,100.8 163.83,100.8 165.09,99.53 186.05,99.53 186.69,100.16 v191.77,100.16
DIML\  (via drill 0.61)
  Top 0.254: v174.62,77.94 174.62,22.06 177.8,18.89 INTENB.11 | v128.27,129.38 128.27,109.05 129.53,107.78 IC17.12 | v175.25,129.38 176.53,129.38 177.8,130.65 193.03,130.65 193.03,78.57 194.94,76.67 FIELD.11
  Bottom 0.254: v174.62,77.94 186.05,77.94 186.69,77.3 193.03,77.3 194.31,76.03 FIELD.11 | v128.27,129.38 v175.25,129.38
DIO00  (via drill 0.61)
  Top 0.254: v66.04,18.89 66.04,21.43 IC39.17 66.04,23.96 64.77,25.23 64.77,36.66 67.31,39.2 67.31,65.88 66.04,67.14 IC27.17 66.04,69.68 v66.04,72.86 | v54.6,83.02 54.6,103.97 55.88,105.24 IC14.12 | v60.95,83.02 62.22,81.75 v62.22,72.86
  Bottom 0.254: IC13.12 36.19,105.88 37.46,104.61 53.97,104.61 55.24,105.88 IC14.12 | IC34.8 16.51,25.23 17.78,26.51 62.22,26.51 65.4,23.33 IC39.17 | v66.04,18.89 76.2,18.89 77.47,20.16 IC35.12 | v60.95,83.02 v54.6,83.02 | v66.04,72.86 v62.22,72.86
DIO01  (via drill 0.61)
  Top 0.254: 57.14,109.05 58.41,107.78 IC14.11 | 57.14,109.05 v55.88,110.32 | v57.14,65.88 v57.14,58.26 | v57.14,70.95 57.14,109.05 | v62.22,27.78 62.22,10 63.49,8.73 IC39.15 | v8.88,29.05 v8.88,69.68
  Bottom 0.254: v55.88,110.32 45.71,110.32 44.45,109.05 40.63,109.05 38.73,107.15 IC13.11 | v57.14,58.26 58.41,58.26 62.86,53.81 IC27.15 | 57.14,70.32 v57.14,70.95 | 57.14,70.32 v57.14,65.88 | 17.78,29.05 16.51,30.32 IC34.6 | 17.78,29.05 26.67,29.05 28.57,27.14 62.22,27.14 | 62.22,27.14 69.21,27.14 69.84,26.51 73.66,26.51 74.93,25.23 77.47,25.23 IC35.14 | 62.22,27.14 v62.22,27.78 | 57.14,70.32 24.76,70.32 24.12,69.68 v8.88,69.68 | v8.88,29.05 17.78,29.05
DIO02  (via drill 0.61)
  Top 0.254: v42.54,103.34 40.63,105.24 IC13.10 | v59.68,34.12 59.68,10 60.95,8.73 IC39.14 | v60.95,48.73 60.95,51.91 IC27.14 | v64.77,47.46 64.77,37.94 63.49,36.66 v63.49,34.12 | v64.77,104.61 67.94,101.43 67.94,84.29 67.31,83.65 67.31,67.14 67.94,66.51 67.94,38.57 66.67,37.3 v66.67,34.12
  Bottom 0.254: v42.54,103.34 43.17,103.97 58.41,103.97 60.32,105.88 IC14.10 61.59,105.88 62.86,104.61 v64.77,104.61 | IC34.4 16.51,35.4 17.78,34.12 v59.68,34.12 v63.49,34.12 v66.67,34.12 73.66,34.12 77.47,30.32 IC35.16 | v60.95,48.73 62.22,47.46 v64.77,47.46
DIO03  (via drill 0.61)
  Top 0.254: v62.22,109.69 63.49,108.42 63.49,107.78 IC14.9 64.13,107.15 65.4,108.42 69.84,108.42 69.84,88.73 70.48,88.1 v70.48,70.32 | v57.14,40.48 v57.14,32.22 57.14,10 58.41,8.73 IC39.13 | v58.41,48.09 58.41,51.91 IC27.13 59.05,53.81 59.05,64.6 v59.68,65.24 | v73.66,30.95 73.66,31.59 77.47,35.4 IC35.18
  Bottom 0.254: v62.22,109.69 61.59,109.05 45.71,109.05 43.81,107.15 IC13.9 | v57.14,40.48 55.88,41.74 19.68,41.74 18.41,40.48 16.51,40.48 IC34.2 13.96,40.48 12.69,39.2 6.34,39.2 6.34,48.73 6.98,49.37 10.79,49.37 12.69,47.46 57.78,47.46 v58.41,48.09 | v73.66,30.95 73.02,31.59 67.31,31.59 66.67,32.22 v57.14,32.22 | v70.48,70.32 65.4,65.24 v59.68,65.24
DIO04  (via drill 0.61)
  Top 0.254: v73.02,42.38 74.29,43.65 74.29,56.35 76.2,58.26 76.2,63.34 | 76.2,63.34 76.2,77.94 72.39,81.75 v72.39,93.81 72.39,96.35 73.66,97.62 IC15.2 | v75.56,63.34 76.2,63.34
  Bottom 0.254: IC26.17 24.12,65.88 24.76,65.24 55.24,65.24 57.14,63.34 69.84,63.34 IC28.3 72.39,63.34 v75.56,63.34 | v73.02,42.38 72.39,43.02 58.41,43.02 56.51,44.92 IC33.21 | v72.39,93.81 58.41,93.81 56.51,91.91 IC23.21
DIO05  (via drill 0.61)
  Top 0.254: IC15.1 71.12,97.62 v71.12,92.54 71.12,70.95 73.02,69.05 73.02,60.16 71.75,58.89 IC28.5 70.48,57.62 69.21,56.35 69.21,44.92 73.02,41.11 73.02,36.66 v69.21,36.66 | v59.68,37.94 59.68,43.02 58.41,44.29 IC33.20
  Bottom 0.254: v71.12,92.54 70.48,93.18 60.32,93.18 59.05,91.91 IC23.20 | v59.68,37.94 60.95,36.66 v69.21,36.66 | IC26.15 24.12,60.8 24.76,60.16 66.67,60.16 68.58,58.26 69.84,58.26 IC28.5
DIO06  (via drill 0.61)
  Top 0.254: v52.06,89.37 52.06,107.78 56.51,112.23 73.66,112.23 73.66,107.78 IC15.13 | v73.02,43.65 73.02,51.27 71.75,52.54 IC28.7 | v26.03,48.73 26.03,52.54 23.49,55.08 IC26.13 | v44.45,79.21 v44.45,89.37 | v19.68,68.41 v19.68,77.94 | v55.88,58.26 v55.88,65.88
  Bottom 0.254: IC23.19 60.32,90.64 59.05,89.37 v52.06,89.37 v44.45,89.37 | v73.02,43.65 62.86,43.65 61.59,44.92 IC33.19 60.95,46.83 58.41,49.37 26.67,49.37 v26.03,48.73 | v44.45,79.21 43.17,77.94 v19.68,77.94 | v19.68,68.41 20.95,67.14 26.67,67.14 27.94,65.88 v55.88,65.88 | v55.88,58.26 53.97,56.35 23.49,56.35 IC26.13
DIO07  (via drill 0.61)
  Top 0.254: IC23.18 63.49,92.54 64.77,93.81 64.77,102.7 62.22,105.24 62.22,108.42 60.95,109.69 62.22,110.96 72.39,110.96 72.39,105.24 73.02,104.61 75.56,104.61 75.56,105.88 IC15.12 | v63.49,50.63 63.49,46.83 IC33.18 | v26.03,88.1 26.03,55.72 v26.67,55.08
  Bottom 0.254: 26.67,50.63 v63.49,50.63 67.31,50.63 69.84,48.09 IC28.9 | 26.67,50.63 24.12,50.63 IC26.11 | v26.03,88.1 26.67,87.46 59.68,87.46 62.86,90.64 IC23.18 | 26.67,50.63 v26.67,55.08
DIO08  (via drill 0.61)
  Top 0.254: 77.47,89.37 77.47,103.97 78.73,105.24 IC15.11 | 77.47,89.37 77.47,82.38 78.73,81.11 78.73,79.21 80.64,77.3 80.64,50 79.37,48.73 IC28.12 | v18.41,55.72 19.68,54.45 v19.68,50.63 | IC23.17 66.04,90 64.77,88.73 64.77,48.73 66.04,47.46 66.04,46.83 IC33.17 | v74.93,89.37 77.47,89.37
  Bottom 0.254: v18.41,55.72 16.51,55.72 IC26.8 | v19.68,50.63 20.95,49.37 25.39,49.37 26.03,50 62.86,50 64.13,48.73 64.77,48.73 66.04,47.46 66.04,46.83 IC33.17 | v74.93,89.37 67.94,89.37 66.67,90.64 IC23.17
DIO09  (via drill 0.61)
  Top 0.254: IC33.15 63.49,31.59 62.22,32.86 v62.22,55.72 62.22,71.59 63.49,72.86 63.49,74.77 IC23.15 63.49,77.3 v63.49,87.46 | v80.01,88.73 80.01,103.97 81.28,105.24 IC15.10
  Bottom 0.254: IC28.14 77.47,53.18 76.2,54.45 67.31,54.45 66.04,55.72 v62.22,55.72 58.41,59.52 17.78,59.52 16.51,60.8 IC26.6 | v80.01,88.73 78.1,86.83 64.13,86.83 v63.49,87.46
DIO10  (via drill 0.61)
  Top 0.254: v81.91,59.52 81.91,81.75 82.55,82.38 82.55,103.97 83.81,105.24 IC15.9 | IC23.14 60.95,74.77 60.95,70.95 59.68,69.68 59.68,67.14 60.95,65.88 60.95,62.7 v60.32,62.06 59.68,61.43 59.68,44.29 60.95,43.02 60.95,31.59 IC33.14 | v73.66,59.52 v74.93,58.26
  Bottom 0.254: v81.91,59.52 81.28,59.52 80.01,58.26 IC28.16 77.47,58.26 v74.93,58.26 | IC26.4 16.51,65.88 20.32,62.06 v60.32,62.06 66.04,62.06 68.58,59.52 v73.66,59.52
DIO11  (via drill 0.61)
  Top 0.254: IC33.13 58.41,31.59 58.41,43.02 57.14,44.29 57.14,56.98 58.41,58.26 v58.41,65.24 58.41,65.88 57.14,67.14 57.14,69.68 58.41,70.95 58.41,74.77 IC23.13 58.41,77.3 58.41,88.73 59.68,90 59.68,109.69 v60.95,110.96
  Bottom 0.254: IC28.18 77.47,63.34 76.2,64.6 60.32,64.6 59.68,63.97 v58.41,65.24 59.68,66.51 59.68,69.68 57.14,72.22 17.78,72.22 16.51,70.95 IC26.2 | v60.95,110.96 81.91,110.96 85.72,107.15 IC15.8
DIOEVEN  (via drill 0.61)
  Top 0.254: v64.77,19.52 63.49,20.79 63.49,21.43 IC39.18 | v39.36,93.81 39.36,100.16 33.65,105.88 IC13.13 | v59.68,88.73 v59.68,70.95 | v8.88,21.43 1.27,21.43 1.27,81.75 v3.17,83.65
  Bottom 0.254: v64.77,19.52 65.4,20.16 69.84,20.16 IC35.9 | 39.36,89.37 39.36,88.1 59.05,88.1 v59.68,88.73 | 39.36,89.37 v39.36,93.81 | v59.68,70.95 60.32,70.32 61.59,70.32 62.86,69.05 IC27.18 | v8.88,21.43 24.12,21.43 27.3,24.6 61.59,24.6 62.86,23.33 IC39.18 | v3.17,83.65 9.52,90 26.67,90 27.3,89.37 39.36,89.37
DMA00  (via drill 0.61)
  Top 0.254: IC23.25 45.71,90 46.98,88.73 46.98,70.95 45.71,69.68 IC27.25 45.71,67.14 45.71,55.72 46.98,54.45 46.98,48.09 45.71,46.83 IC33.25 45.71,44.29 45.71,32.86 46.98,31.59 46.98,25.23 45.71,23.96 IC39.25 45.71,21.43 46.98,20.16 46.98,1.74 100.96,1.74 v106.68,7.46
  Bottom 0.254: IC38.8 151.12,10 149.86,10 148.59,8.73 138.43,8.73 135.88,6.18 130.81,6.18 130.17,6.82 126.36,6.82 125.73,7.46 DMA0-3.7 123.19,7.46 v106.68,7.46
DMA01  (via drill 0.61)
  Top 0.254: v121.28,16.98 121.28,13.17 123.82,10.63 DMA0-3.6 | IC23.23 50.79,90 50.79,84.92 52.7,83.02 52.7,77.94 52.06,77.3 52.06,70.95 50.79,69.68 IC27.23 50.79,67.14 51.43,66.51 51.43,55.08 52.06,54.45 52.06,48.09 50.79,46.83 IC33.23 50.79,44.29 50.79,32.86 52.06,31.59 52.06,25.23 50.79,23.96 IC39.23 51.43,22.06 51.43,9.36 52.06,8.73 52.06,5.55 66.67,5.55 67.31,6.18 67.31,7.46 v67.94,8.09
  Bottom 0.254: v121.28,16.98 123.19,18.89 125.73,18.89 128.27,16.35 149.86,16.35 151.12,15.08 IC38.6 | v67.94,8.09 69.21,9.36 87.62,9.36 88.26,10 123.19,10 DMA0-3.6
DMA02  (via drill 0.61)
  Top 0.254: IC39.26 43.17,23.96 44.45,25.23 44.45,31.59 43.17,32.86 v43.17,39.84 43.17,44.29 IC33.26 43.17,46.83 44.45,48.09 44.45,54.45 43.17,55.72 43.17,67.14 IC27.26 43.17,69.68 44.45,70.95 44.45,77.94 43.17,79.21 43.17,90 IC23.26 | v93.98,16.98 90.17,16.98 v90.17,35.4
  Bottom 0.254: IC38.4 151.12,20.16 149.86,18.89 127,18.89 125.73,20.16 DMA0-3.2 123.19,20.16 120.01,16.98 v93.98,16.98 | v90.17,35.4 88.9,36.66 74.93,36.66 72.39,39.2 43.81,39.2 v43.17,39.84
DMA03  (via drill 0.61)
  Top 0.254: v126.36,25.23 126.36,19.52 125.09,18.25 DMA0-3.3 | IC39.27 40.63,23.96 41.9,25.23 41.9,38.57 40.63,39.84 40.63,44.29 IC33.27 40.63,46.83 41.9,48.09 41.9,54.45 40.63,55.72 40.63,67.14 IC27.27 40.63,69.68 41.9,70.95 41.9,88.73 40.63,90 IC23.27 | v90.17,15.71 88.9,16.98 v88.9,44.92 | v74.29,41.11 73.66,40.48 73.66,32.86 72.39,31.59 69.21,31.59 69.21,29.68 69.84,29.05 74.29,29.05 74.29,23.33 72.39,21.43 v69.21,21.43
  Bottom 0.254: v126.36,25.23 151.12,25.23 IC38.2 | v90.17,15.71 121.28,15.71 123.19,17.62 DMA0-3.3 | v88.9,44.92 88.26,44.29 77.47,44.29 v74.29,41.11 | v69.21,21.43 68.58,20.79 42.54,20.79 41.27,22.06 IC39.27
DMA04  (via drill 0.61)
  Top 0.254: v141.6,34.12 142.87,35.4 v142.87,39.2 | IC23.5 38.09,74.77 38.09,70.95 36.82,69.68 36.82,67.14 37.46,66.51 37.46,55.08 38.09,54.45 IC27.5 38.09,51.91 38.09,48.09 36.82,46.83 36.82,44.29 37.46,43.65 37.46,32.22 38.09,31.59 IC33.5 38.09,29.05 38.09,25.23 36.82,23.96 36.82,10 38.09,8.73 IC39.5 38.73,6.82 v41.27,4.28 | v110.48,3.01 125.09,3.01 128.27,6.18 128.27,26.51 125.73,29.05 125.73,34.12 126.36,34.76 126.36,36.03 125.09,37.3 DMA4-7.7
  Bottom 0.254: v141.6,34.12 129.53,34.12 125.73,37.94 DMA4-7.7 | v142.87,39.2 149.86,39.2 151.12,40.48 IC31.8 | v110.48,3.01 109.22,1.74 43.81,1.74 v41.27,4.28
DMA05  (via drill 0.61)
  Top 0.254: IC39.6 40.63,8.73 39.36,10 39.36,27.78 40.63,29.05 IC33.6 40.63,31.59 39.36,32.86 39.36,46.83 40.63,48.09 40.63,51.91 IC27.6 40.63,54.45 39.36,55.72 39.36,69.68 40.63,70.95 40.63,74.77 IC23.6 40.63,77.3 40.63,87.46 39.36,88.73 39.36,92.54 v41.27,94.45 | v121.28,40.48 120.01,41.74 120.01,49.37 120.65,50 120.65,57.62 118.74,59.52 118.74,81.75 119.38,82.38 v119.38,95.72
  Bottom 0.254: IC31.6 151.12,45.55 149.86,46.83 144.78,46.83 142.24,44.29 138.43,44.29 135.88,41.74 130.81,41.74 130.17,41.11 126.36,41.11 125.73,40.48 DMA4-7.6 123.19,40.48 v121.28,40.48 | v119.38,95.72 118.74,96.35 60.95,96.35 59.05,94.45 v41.27,94.45
DMA06  (via drill 0.61)
  Top 0.254: IC23.7 43.17,74.77 43.17,70.95 41.9,69.68 41.9,55.72 43.17,54.45 IC27.7 43.17,51.91 43.17,48.09 41.9,46.83 41.9,39.84 42.54,39.2 42.54,32.22 43.17,31.59 IC33.7 43.17,29.05 43.17,25.23 41.9,23.96 41.9,10 43.17,8.73 IC39.7 43.17,6.18 v45.08,4.28 | v118.74,50.63 118.11,50 v118.11,4.28
  Bottom 0.254: IC31.4 151.12,50.63 149.86,49.37 146.05,49.37 143.5,46.83 129.53,46.83 125.73,50.63 DMA4-7.2 123.19,50.63 v118.74,50.63 | v118.11,4.28 99.69,4.28 97.15,6.82 70.48,6.82 67.94,4.28 v45.08,4.28
DMA07  (via drill 0.61)
  Top 0.254: v126.36,55.08 126.36,50 125.09,48.73 DMA4-7.3 | IC39.8 45.71,8.73 44.45,10 v44.45,16.98 44.45,23.96 45.71,25.23 45.71,29.05 IC33.8 45.71,31.59 44.45,32.86 44.45,46.83 45.71,48.09 45.71,51.91 IC27.8 45.71,54.45 44.45,55.72 44.45,69.68 45.71,70.95 45.71,74.77 IC23.8 | v109.22,40.48 107.95,39.2 107.95,36.03 102.87,30.95 102.87,6.18 100.96,4.28 95.88,4.28 95.88,16.35 93.98,18.25 v92.7,18.25
  Bottom 0.254: v126.36,55.08 128.9,57.62 145.41,57.62 147.31,55.72 151.12,55.72 IC31.2 | v109.22,40.48 110.48,40.48 110.48,46.19 113.66,49.37 121.92,49.37 123.19,48.09 DMA4-7.3 | v92.7,18.25 80.64,18.25 80.01,18.89 77.47,18.89 74.93,16.35 45.08,16.35 v44.45,16.98
DMA08  (via drill 0.61)
  Top 0.254: v126.36,61.43 126.36,66.51 125.09,67.78 DMA8-11.7 | v151.76,62.06 154.3,64.6 154.3,69.05 153.03,70.32 IC24.8 | IC39.9 48.25,8.73 47.62,9.36 47.62,20.79 46.98,21.43 46.98,23.96 48.25,25.23 48.25,29.05 IC33.9 48.25,31.59 46.98,32.86 46.98,46.83 48.25,48.09 48.25,51.91 IC27.9 48.25,54.45 46.98,55.72 46.98,69.68 48.25,70.95 48.25,74.77 IC23.9 | v120.65,62.06 120.01,62.7 120.01,73.49 v120.65,74.13
  Bottom 0.254: v151.76,62.06 138.43,62.06 137.79,61.43 v126.36,61.43 125.73,62.06 v120.65,62.06 | v120.65,74.13 70.48,74.13 66.67,77.94 55.24,77.94 54.6,77.3 54.6,74.13 52.7,74.13 52.06,74.77 52.06,77.94 50.16,77.94 48.89,76.67 IC23.9
DMA09  (via drill 0.61)
  Top 0.254: IC39.10 50.79,8.73 50.79,20.16 49.52,21.43 49.52,27.78 50.79,29.05 IC33.10 50.79,31.59 49.52,32.86 49.52,49.37 50.79,50.63 50.79,51.91 IC27.10 50.79,54.45 49.52,55.72 49.52,73.49 50.79,74.77 IC23.10 | v115.56,70.95 114.93,71.59 v114.93,75.4 | v72.39,78.57 v74.93,76.03
  Bottom 0.254: IC24.6 151.12,76.03 149.86,77.3 138.43,77.3 135.88,74.77 130.17,74.77 130.17,72.86 127.63,70.32 126.36,70.32 125.73,70.95 DMA8-11.6 123.19,70.95 v115.56,70.95 | v114.93,75.4 114.3,76.03 v74.93,76.03 | v72.39,78.57 71.75,79.21 48.89,79.21 46.98,77.3 46.98,74.13 48.89,74.13 50.16,75.4 IC23.10
DMA10  (via drill 0.61)
  Top 0.254: IC39.11 53.34,8.73 52.06,10 52.06,23.96 53.34,25.23 53.34,29.05 IC33.11 53.34,31.59 52.06,32.86 52.06,46.83 53.34,48.09 53.34,51.91 IC27.11 53.34,54.45 52.06,55.72 52.06,69.68 53.34,70.95 53.34,74.77 IC23.11 | v120.65,80.48 121.28,79.84 121.28,77.94 v120.65,77.3
  Bottom 0.254: IC24.4 151.12,81.11 149.86,81.11 148.59,79.84 130.81,79.84 130.17,80.48 126.36,80.48 125.73,81.11 DMA8-11.2 123.19,81.11 122.55,80.48 v120.65,80.48 | v120.65,77.3 68.58,77.3 67.31,78.57 54.6,78.57 53.34,77.3 IC23.11
DMA11  (via drill 0.61)
  Top 0.254: v127.63,78.57 130.17,81.11 130.17,90 v132.71,92.54 | v153.66,92.54 154.3,91.91 154.3,88.1 153.03,86.83 IC24.2 | IC39.12 55.88,8.73 55.88,20.16 54.6,21.43 54.6,27.78 55.88,29.05 IC33.12 55.88,31.59 54.6,32.86 54.6,50.63 | 54.6,50.63 55.88,51.91 IC27.12 | 54.6,50.63 54.6,73.49 55.88,74.77 IC23.12 | v105.41,72.86 105.41,69.68 v103.5,67.78 | v69.21,71.59 68.58,72.22 v68.58,74.13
